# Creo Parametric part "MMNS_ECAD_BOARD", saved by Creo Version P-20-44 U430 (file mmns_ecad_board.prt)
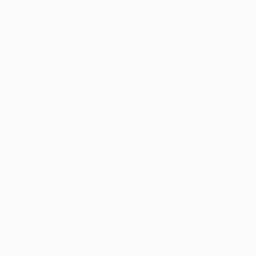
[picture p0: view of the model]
Units: millimeter Newton Second (mmNs); MM, TONNE, SECS

Other parameters: BOARD_THICKNESS, BOARD_BEND_ALLOWANCE_FACTOR, BOARD_BEND_RADIUS, BOARD_BEND_ANGLE, BOARD_BEND_REL_WIDTH, BOARD_BEND_REL_DEPTH

Created from: MMNS_PART_SHEETMETAL.PRT

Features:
  1. datum plane "RIGHT"
  2. datum plane "TOP"
  3. datum plane "FRONT"
  4. coordinate system

Other named items: CS0

Surfaces: 3 plane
